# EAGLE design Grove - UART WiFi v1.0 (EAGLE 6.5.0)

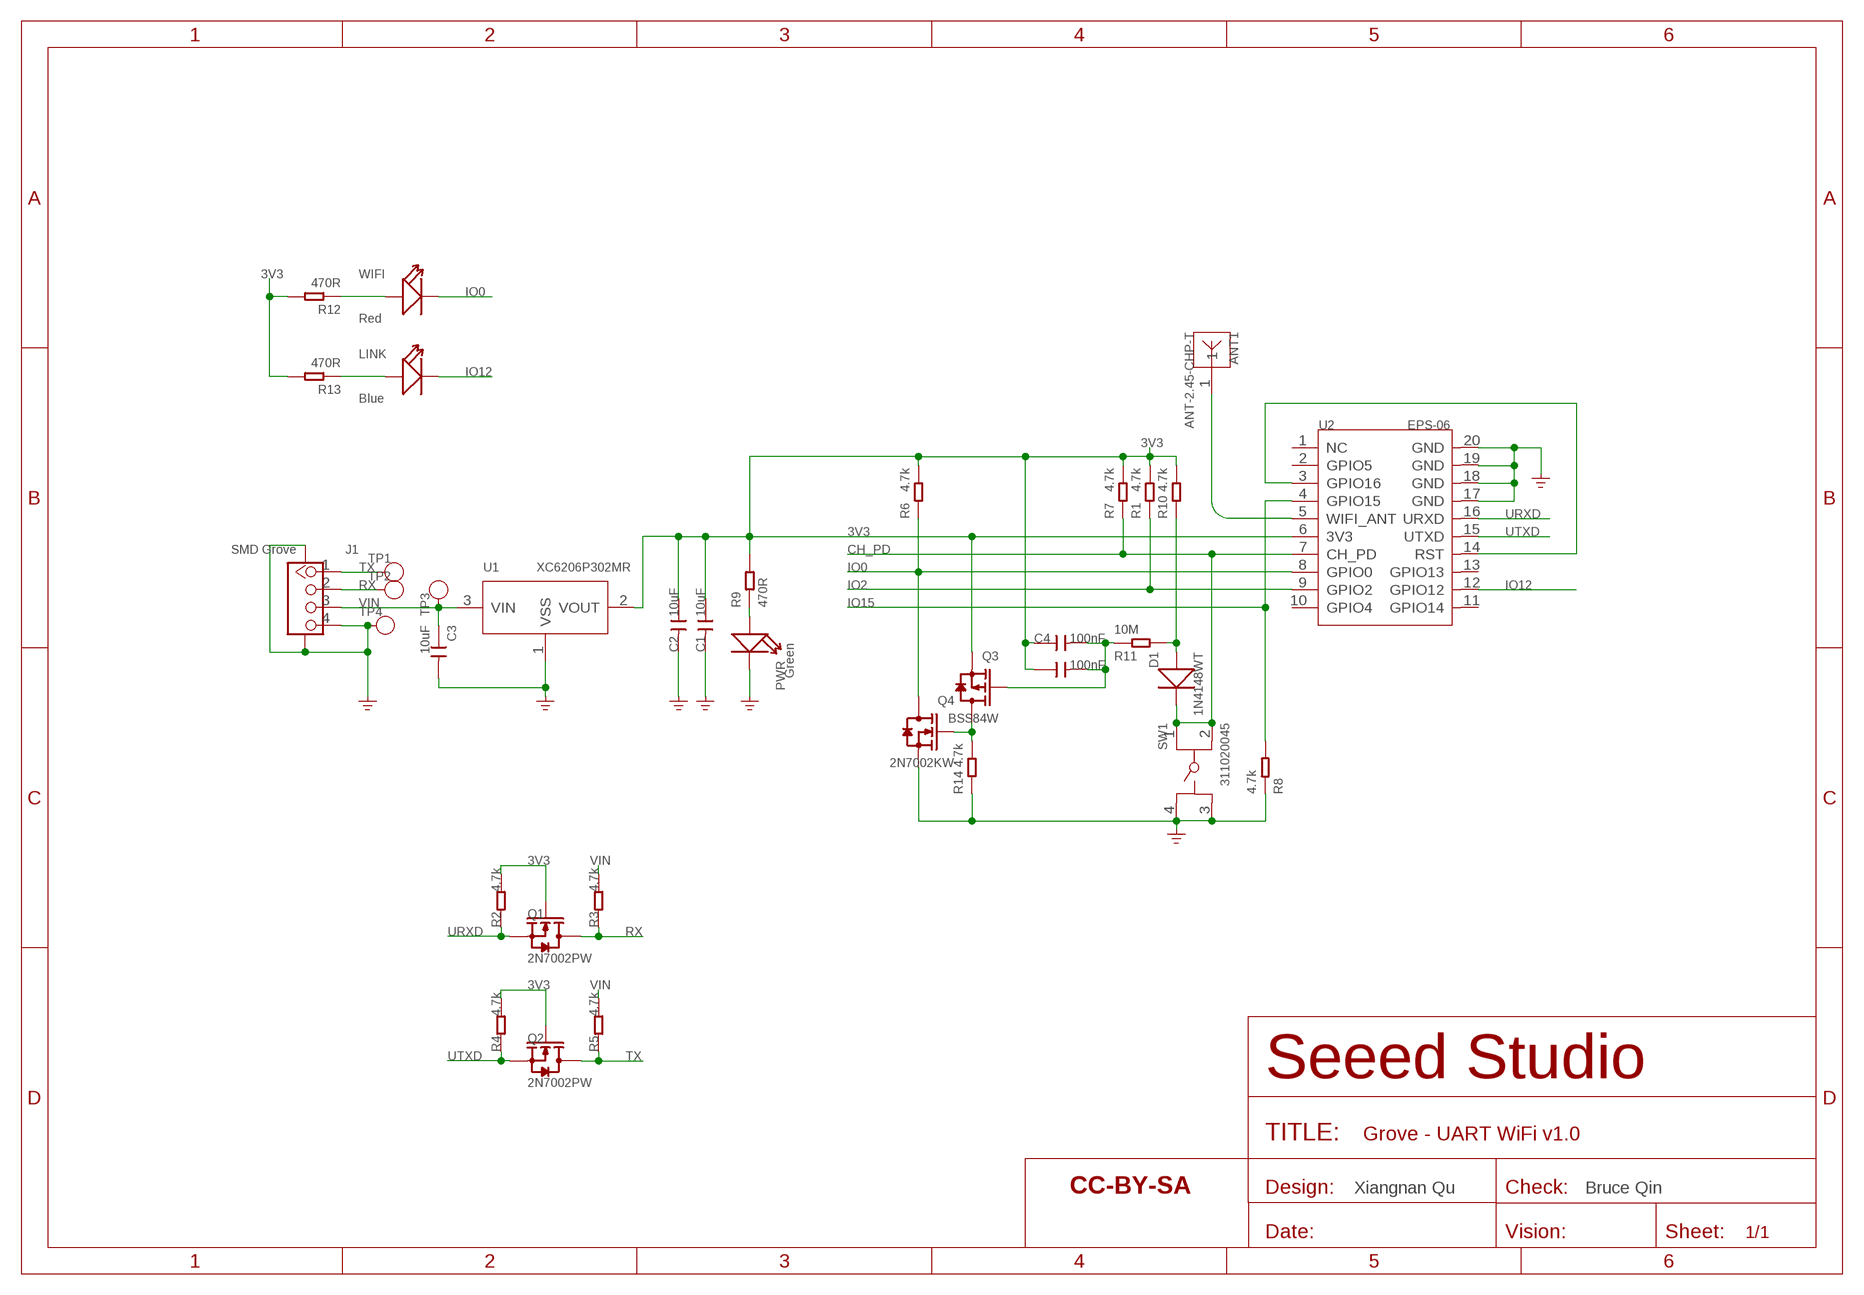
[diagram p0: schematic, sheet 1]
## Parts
ANT1  ANT-2.45-CHP-T  ANT-2.4G-CHP  [ANTENNA-2.4G-L6.5XW2.2MM]
C1  10uF  CAP-0805  [C0805]
C2  10uF  CAP-0805  [C0805]
C3  10uF  CAP-0805  [C0805]
C4  100nF  CAP-0402  [C0402]
C5  100nF  CAP-0402  [C0402]
D1  1N4148WT  DIODE'0603'  [SOD-523]
J1  SMD Grove  GROVE-CONNECTOR-SMD'DD'  [HW4-SMD-2.0]
LINK  Blue  LED'0402'  [LED-0402]
PWR  Green  LED'0402'  [LED-0402]
Q1  2N7002PW  MOSFET-N'SI1304BDL'  [SOT-323]
Q2  2N7002PW  MOSFET-N'SI1304BDL'  [SOT-323]
Q3  BSS84W  MOSFET-P-SOT323  [SOT-323]
Q4  2N7002KW  MOSFET-N'SI1304BDL'  [SOT-323]
R1  4.7k  RES-0402  [R0402]
R2  4.7k  RES-0402  [R0402]
R3  4.7k  RES-0402  [R0402]
R4  4.7k  RES-0402  [R0402]
R5  4.7k  RES-0402  [R0402]
R6  4.7k  RES-0402  [R0402]
R7  4.7k  RES-0402  [R0402]
R8  4.7k  RES-0402  [R0402]
R9  470R  RES-0402  [R0402]
R10  4.7k  RES-0402  [R0402]
R11  10M  RES-0402  [R0402]
R12  470R  RES-0402  [R0402]
R13  470R  RES-0402  [R0402]
R14  4.7k  RES-0402  [R0402]
SW1  311020045  BUTTON-4P  [BUTTON4P-SMD-4.5X3.2X2.5MM]
TP1  TEST-POINT'4545'  [TP-D45MIL]
TP2  TEST-POINT'4545'  [TP-D45MIL]
TP3  TEST-POINT'4545'  [TP-D45MIL]
TP4  TEST-POINT'4545'  [TP-D45MIL]
U1  XC6206P302MR  PMIC-XC6206PMR  [SOT-23]
U2  EPS-06  MOUDLE-WIFI-ESP8266_06  [WIFI20-SMD-16.3X13.1MM]
U$7  SEEEDSTUDIO-OPEN-SCH-FRAME  [SEEEDSTUDIO-PCB-FRAME]
WIFI  Red  LED'0402'  [LED-0402]

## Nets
3V3: C1.1 C2.1 C4.1 C5.1 Q1.1(G) Q2.1(G) Q3.2(S) R1.2 R2.2 R4.2 R6.2 R7.2 R9.2 R10.2 R12.2 R13.2 U1.2(VOUT) U2.6(3V3)
CH_PD: D1.- R7.1 SW1.1 SW1.2 U2.7(CH_PD)
GND: C1.2 C2.2 C3.2 J1.4 J1.SS1 J1.SS2 PWR.- Q4.2(S) R8.1 R14.1 SW1.3 SW1.4 TP4.T U1.1(VSS) U2.17(GND) U2.18(GND) U2.19(GND) U2.20(GND) ; supply symbol labelled GND_POWER
IO0: Q4.3(D) R6.1 U2.8(GPIO0) WIFI.-
IO2: R1.1 U2.9(GPIO2)
IO12: LINK.- U2.12(GPIO12)
IO15: R8.2 U2.4(GPIO15)
N$1: ANT1.1 U2.5(WIFI_ANT)
N$2: D1.+ R10.1 R11.2
N$3: PWR.+ R9.1
N$4: R12.1 WIFI.+
N$5: LINK.+ R13.1
N$6: Q3.3(D) Q4.1(G) R14.2
N$8: U2.3(GPIO16) U2.14(RST)
N$10: C4.2 C5.2 Q3.1(G) R11.1
RX: J1.2 Q1.3(D) R3.1 TP2.T
TX: J1.1 Q2.3(D) R5.1 TP1.T
URXD: Q1.2(S) R2.1 U2.16(URXD)
UTXD: Q2.2(S) R4.1 U2.15(UTXD)
VIN: C3.1 J1.3 R3.2 R5.2 TP3.T U1.3(VIN)
Unconnected: U2.1(NC) U2.2(GPIO5) U2.10(GPIO4) U2.11(GPIO14) U2.13(GPIO13)

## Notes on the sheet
- Xiangnan Qu | Bruce Qin

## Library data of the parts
ANT1 = template:ANT-2.4G-CHP
C1-C5 = Discrete-new:CAP: Ceramic Capacitors
D1 = Discrete-new:DIODE*
J1 = Connector-new:GROVE-CONNECTOR-SMD: 4P-SMD-2.0:320110030;4P-SMD-2.0-90D:320110032
LINK PWR WIFI = Discrete-new:LED
Q1 Q2 Q4 = Discrete-new:MOSFET-N
Q3 = Discrete-new:MOSFET-P
R1-R14 = Discrete-new:RES
SW1 = template:BUTTON-4P
TP1-TP4 = Discrete-new:TEST-POINT; PARTNO: DNP
U1 = IC-new:PMIC-XC6206P: LOW ESR Cap.Compatible Positive Voltage Regulators
U2 = template:MOUDLE-WIFI-ESP8266_06
U$7 = moudle-new:SEEEDSTUDIO-OPEN-SCH-FRAME

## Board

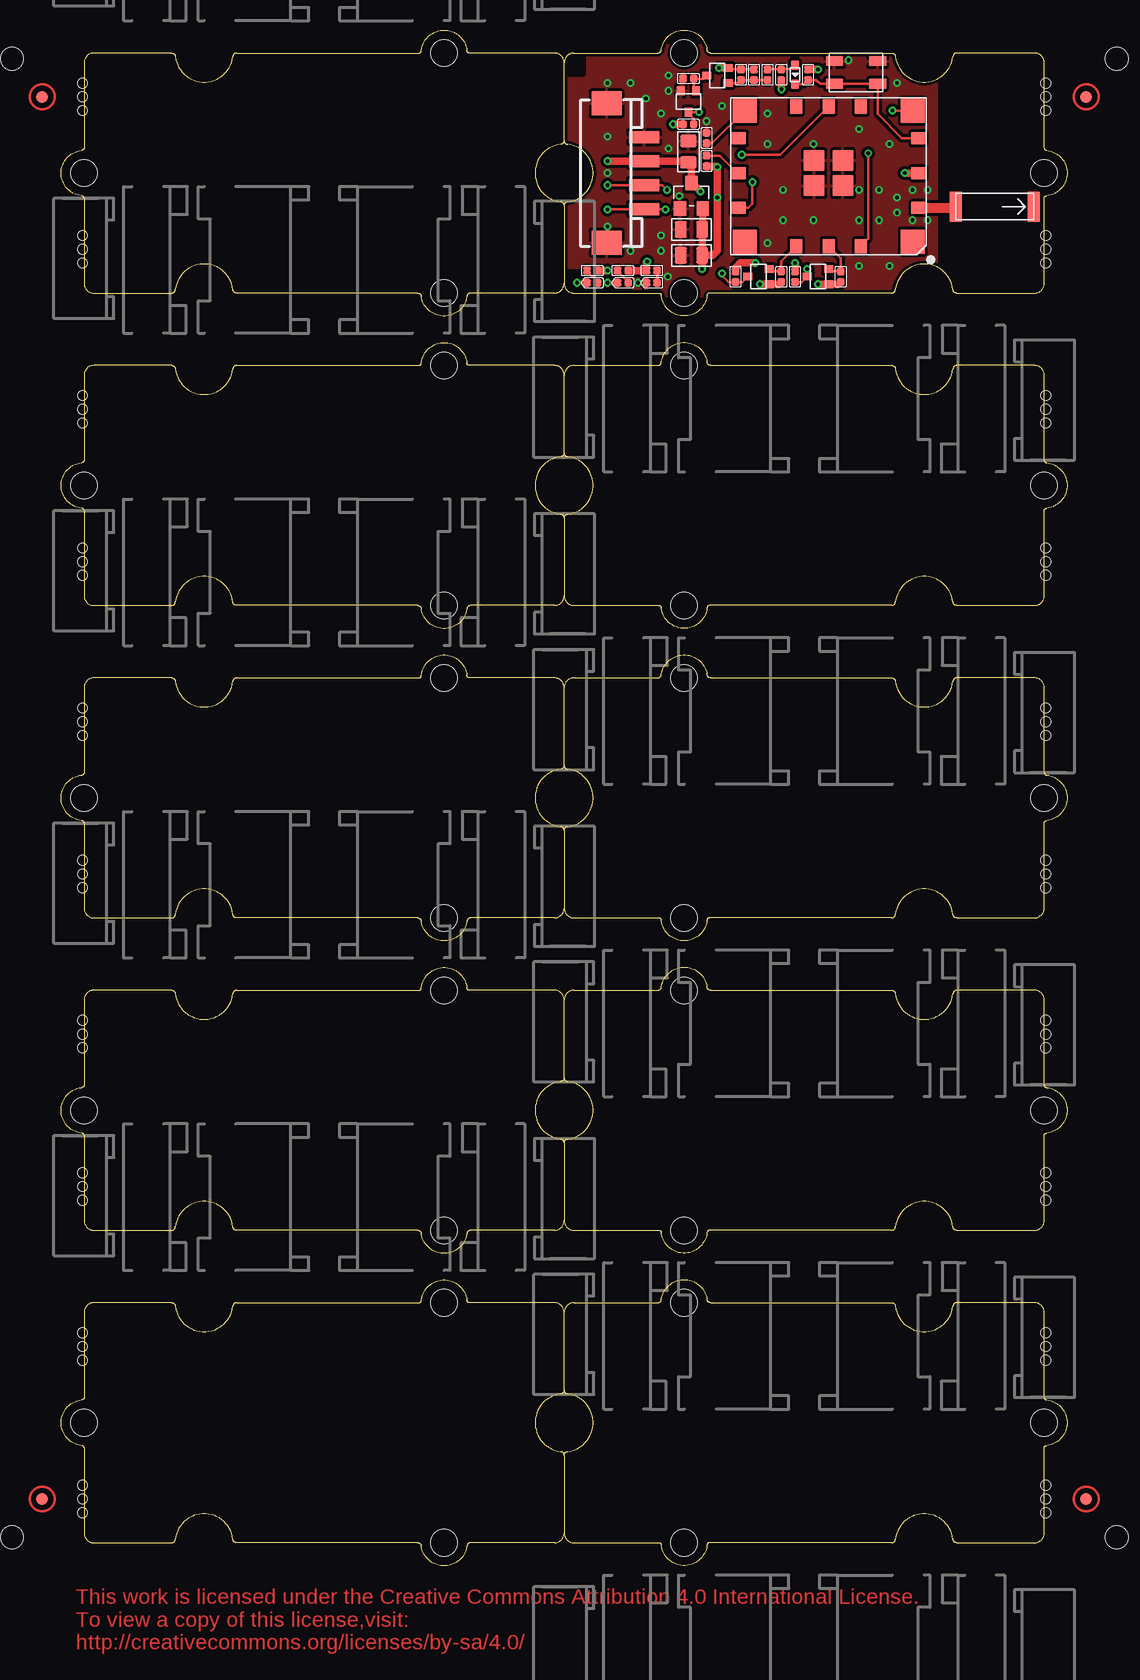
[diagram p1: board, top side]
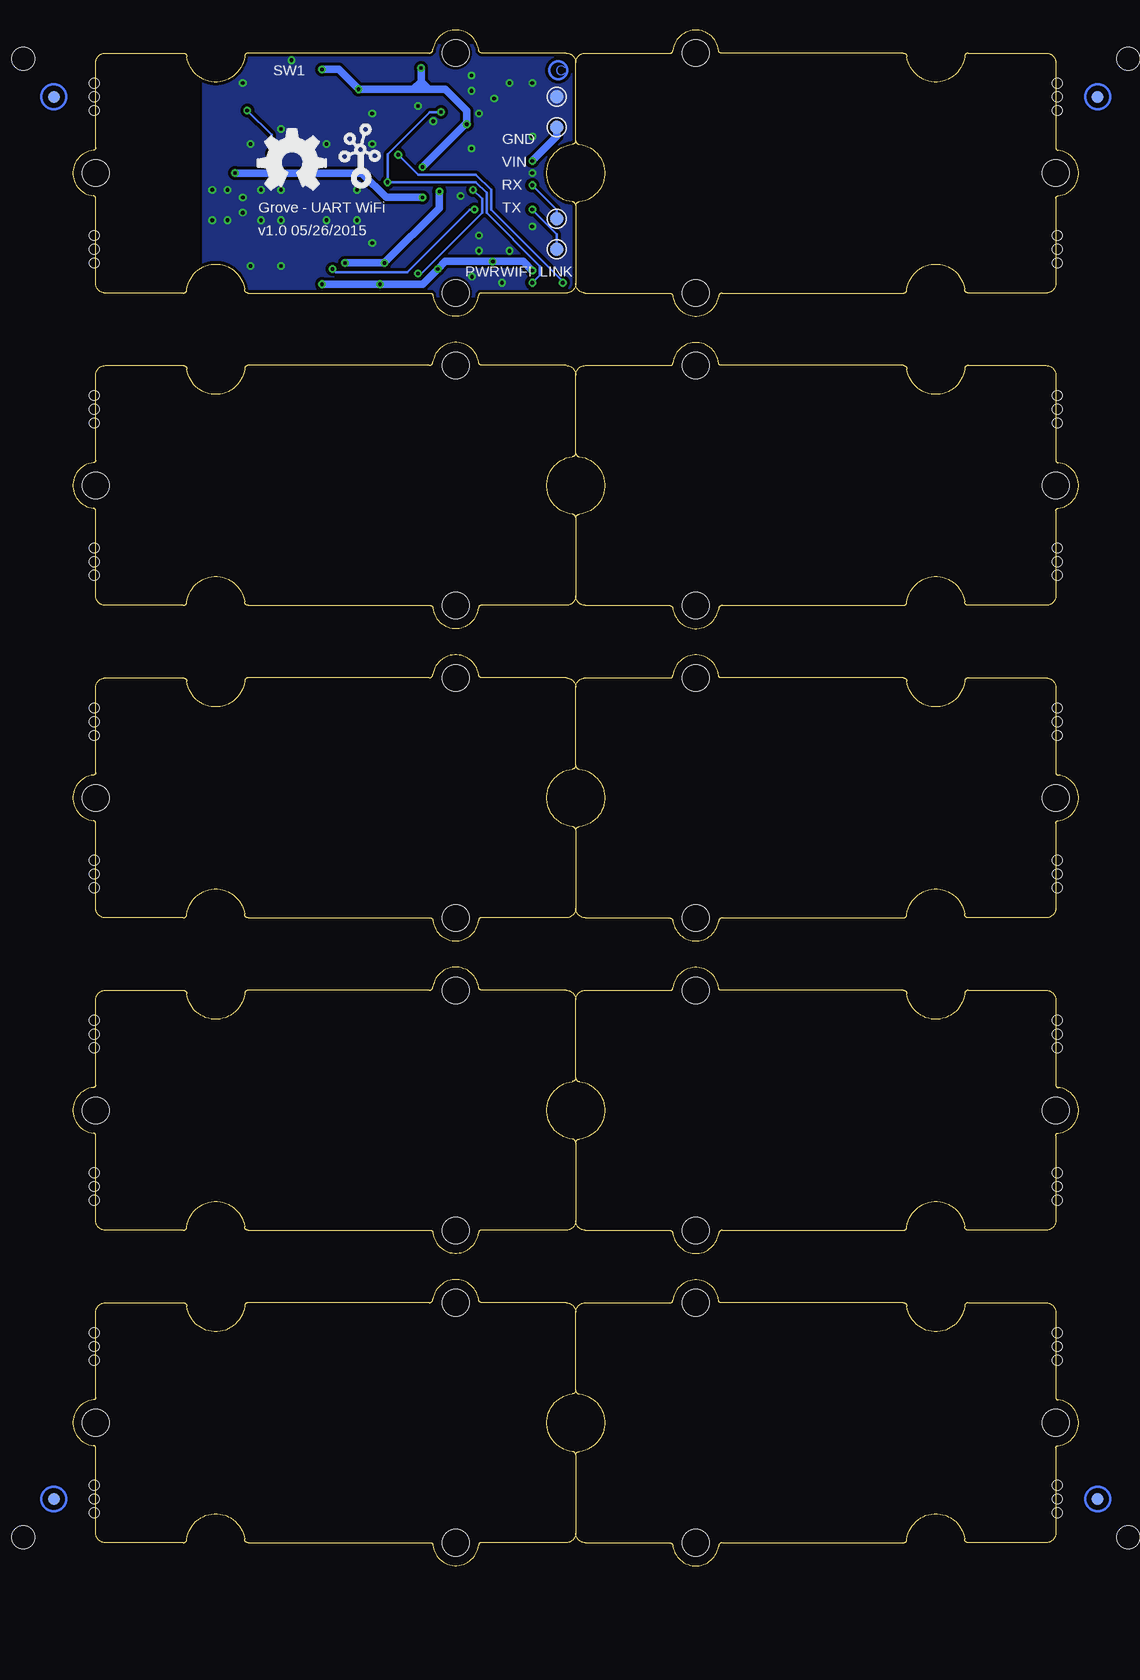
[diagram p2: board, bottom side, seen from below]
Size 83.82 x 127.98 mm. Coordinates in mm from the lower left corner, seen from the top.
Copper layers (1*16): Top 0.035mm / dielectric 1.5mm / Bottom 0.035mm
Design rules "SeeedStudio_2layer_DRU_no_angle_20140221 *": minimum track width 6mil, minimum drill 12mil, track to track 6mil, track to pad 6mil, pad to pad 6mil, via to via 6mil, smd to smd 0mil, copper to edge 10mil, drill to drill 10mil, minimum pad ring 10mil, minimum via ring 6mil, stop-mask expansion 2mil, vias tented up to drill 25mil, thermal gap 10mil
Holes 0.8 mm at 1.78,123.55 1.78,121.27 1.78,122.41 1.78,110.85 1.78,108.57 1.78,109.71 1.78,97.52 1.78,95.23 1.78,96.38 1.78,84.82 1.78,82.53 1.78,83.68 1.78,71.48 1.78,69.2 1.78,70.34 1.78,58.78 1.78,56.5 1.78,57.64 1.78,45.45 1.78,43.16 1.78,44.31 1.78,32.75 1.78,30.46 1.78,31.61 1.78,19.41 1.78,17.13 1.78,18.27 1.78,6.71 1.78,4.43 1.78,5.57 82.04,121.27 82.04,123.55 82.04,122.41 82.04,108.57 82.04,110.85 82.04,109.71 82.04,95.23 82.04,97.52 82.04,96.38 82.04,82.53 82.04,84.82 82.04,83.68 82.04,69.2 82.04,71.48 82.04,70.34 82.04,56.5 82.04,58.78 82.04,57.64 82.04,43.16 82.04,45.45 82.04,44.31 82.04,30.46 82.04,32.75 82.04,31.61 82.04,17.13 82.04,19.41 82.04,18.27 82.04,4.43 82.04,6.71 82.04,5.57
Holes 1.91 mm at -4.13,2.4 87.95,2.4 87.95,125.59 -4.13,125.59

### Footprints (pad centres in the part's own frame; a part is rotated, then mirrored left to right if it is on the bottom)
ANTENNA-2.4G-L6.5XW2.2MM = smd 2.5 x 1: 1 0,3.25; 2 0,-3.25
C0805 = smd 1.397 x 1.016: 1 0,0.889; 2 0,-0.889
C0402 = smd 0.635 x 0.635: 1 0,0.445; 2 0,-0.445
SOD-523 = smd 0.762 x 0.7: + -0.8,0; - 0.8,0
HW4-SMD-2.0 = smd 1 x 2.5: 1 -3,0; 2 -1,0; 3 1,0; 4 3,0 | smd 2 x 2.5: SS1 -5.8,3.123; SS2 5.8,3.123
LED-0402 = smd 0.635 x 0.635: + -0.445,0; - 0.445,0
ROUND-MARK-1.0 = smd 1.016 x 1.016: P$1 0,0
SOT-323 = smd 0.635 x 0.762: 1 -0.635,-0.889; 2 0.635,-0.889; 3 0,0.889
R0402 = smd 0.635 x 0.635: 1 0,0.445; 2 0,-0.445
BUTTON4P-SMD-4.5X3.2X2.5MM = smd 1.4 x 0.8: 1 -1.8,-0.94; 2 1.8,-0.94; 3 1.8,0.94; 4 -1.8,0.94
TP-D45MIL = smd 1.143 x 1.143: T 0,0
SOT-23 = smd 1.016 x 1.2: 1 -0.95,-1.06; 2 0.95,-1.06; 3 0,1.06
WIFI20-SMD-16.3X13.1MM = smd 2 x 2: 1 -7,5.708; 2 7,5.708; 3 -7,-5.2; 4 7,-5.2 | smd 1.2 x 1: 5 -7.493,2.9; 6 -7.493,0; 7 -7.493,-2.9; 8 7.493,2.9; 9 7.493,0; 10 7.493,-2.9 | smd 1 x 1.2: 11 -2.7,-5.558; 12 0,-5.558; 13 2.7,-5.558; 14 -2.7,6.096; 15 0,6.096; 16 2.7,6.096 | smd 1.7 x 1.7: 17 -1.2,1.05; 18 1.2,1.05; 19 -1.2,-1.05; 20 1.2,-1.05
GROVE-TEST-PLATFORM = hole 2.2: -10,-10; -10,10; 20,0
GROVE-1*2-TEST-PLATFORM = hole 2.2: -10,-10; -10,10; 20,0

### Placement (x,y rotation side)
ANT1  77.79,113.27 90 top
C1  52.52,109.2 270 top
C2  52.52,111.36 270 top
C3  52.26,117.84 180 top
C4  56.64,124.25 0 top
C5  57.72,124.25 0 top
D1  61.15,124.25 270 top
J1  48.58,116.06 90 top
LINK  44.26,106.92 180 top
P1  [ROUND-MARK-1.0]  -1.59,5.57 0 top
P2  [ROUND-MARK-1.0]  85.41,5.57 0 top
P3  [ROUND-MARK-1.0]  -1.59,122.41 0 top
P4  [ROUND-MARK-1.0]  85.41,122.41 0 top
P5  [ROUND-MARK-1.0]  -1.59,5.57 0 bottom
P6  [ROUND-MARK-1.0]  85.41,5.57 0 bottom
P7  [ROUND-MARK-1.0]  85.41,122.41 0 bottom
P8  [ROUND-MARK-1.0]  -1.59,122.41 0 bottom
PWR  49.21,106.92 180 top
Q1  58.1,107.43 90 top
Q2  63.06,107.43 90 top
Q3  54.67,124.19 90 top
Q4  52.26,122.03 180 top
R1  53.79,117.08 0 top
R2  60.01,107.43 0 top
R3  56.2,107.43 180 top
R4  64.96,107.43 0 top
R5  61.15,107.43 180 top
R6  52.26,120.13 270 top
R7  62.23,124.25 180 top
R8  53.79,118.98 0 top
R9  49.21,107.93 270 top
R10  60.01,124.25 0 top
R11  58.87,124.25 180 top
R12  46.8,107.93 90 top
R13  44.26,107.93 90 top
R14  52.26,123.94 90 top
SW1  66.23,124.44 0 top
TP1  43.5,109.71 0 bottom
TP2  43.5,112.25 0 bottom
TP3  43.5,119.87 0 bottom
TP4  43.5,122.41 0 bottom
U1  52.52,114.16 0 top
U2  63.95,116.06 180 top
U3  [GROVE-TEST-PLATFORM]  61.91,37.96 0 top
U4  [GROVE-TEST-PLATFORM]  21.91,37.96 180 top
U5  [GROVE-TEST-PLATFORM]  61.91,63.99 0 top
U6  [GROVE-TEST-PLATFORM]  21.91,63.99 180 top
U7  [GROVE-TEST-PLATFORM]  61.91,90.03 0 top
U8  [GROVE-TEST-PLATFORM]  21.91,90.03 180 top
U9  [GROVE-TEST-PLATFORM]  21.91,116.06 180 top
U10  [GROVE-TEST-PLATFORM]  61.91,116.06 0 top
U11  [GROVE-TEST-PLATFORM]  61.91,11.92 0 top
U12  [GROVE-TEST-PLATFORM]  21.91,11.92 180 top
U$7  not placed on the board
U$8  [GROVE-1*2-TEST-PLATFORM]  61.91,116.06 0 top
U$11  [GROVE-SILK-SMALL]  62.04,114.66 0 bottom
U$12  [OSHW_FILLX200_NOTEXT]  68.39,114.66 0 bottom
WIFI  46.8,106.92 180 top

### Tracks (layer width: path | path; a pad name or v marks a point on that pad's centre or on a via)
3V3  (via drill 0.3 pad 0.64)
  Top 0.203: C5.1 C4.1 55.56,124.7 Q3.2
  Top 0.61: U1.2 53.47,111.42 C2.1 C1.1 | R12.2 R9.2 48.77,108.63 v48.83,108.7 | R13.2 v45.53,107.93 | R6.2 v50.99,120.13 | Q3.2 v54.8,124.82 | R10.2 v60.01,123.05 | R7.2 v63.06,124.7 | R2.2 59.82,106.79 Q1.1 v58.23,106.79 | v63.06,106.79 Q2.1 64.77,106.79 R4.2 | v70.3,116.06 U2.6 | C1.1 54.29,109.2 54.67,109.58 v54.67,114.03 v54.67,116.57 54.61,116.63 R1.2 | C1.1 v53.4,108.06
  Bottom 0.61: v45.53,107.93 46.29,108.7 v48.83,108.7 52.77,108.7 v53.4,108.06 54.67,106.79 v58.23,106.79 v63.06,106.79 | 55.44,123.05 v60.01,123.05 61.66,124.7 v63.06,124.7 | 55.44,123.05 54.8,123.05 | 54.8,123.05 54.17,123.05 | 54.17,123.05 52.77,123.05 50.99,121.27 v50.99,120.13 51.12,120.13 v54.67,116.57 | v54.8,124.82 54.8,123.68 | 54.8,123.68 54.8,123.05 | 54.8,123.68 54.17,123.05 | 54.8,123.68 55.44,123.05 | v70.3,116.06 59.75,116.06 57.72,114.03 v54.67,114.03
CH_PD
  Top 0.203: D1.- 61.88,123.45 R7.1 62.93,123.81 63.23,123.5 SW1.1 SW1.2 68.03,120.99 70.06,118.96 U2.7
GND  (via drill 0.3 pad 0.64)
  other vias: 45.53,123.55 58.87,121.01 72.2,112.12 70.93,112.12 69.66,112.76 69.66,114.03 70.93,114.66 72.2,114.66 48.07,106.92 49.98,109.58 47.44,109.58 49.98,110.85 51.5,114.16 50.61,118.09 53.79,120.38 50.61,122.92 50.61,124.19 65.6,125.46 69.66,123.55 50.55,107.43 47.44,123.55 49.98,121.01 48.71,122.28 58.87,118.47 62.68,118.47 66.49,119.74 66.49,114.66 66.49,112.12 62.68,112.12 60.14,112.12 60.14,114.66 66.49,108.31 69.03,108.31 69.03,118.47 58.87,110.22 45.53,116.06 45.53,111.62 45.53,119.11 55.06,121.65 68.14,112.12 68.14,114.66
  pour Top (isolate 0.254, rank 6): 41.72,126.73 72.96,126.73 72.96,105.77 41.72,105.77
  pour Bottom (isolate 0.254, rank 6): 41.72,126.73 72.96,126.73 72.96,105.77 41.72,105.77
IO0  (via drill 0.3 pad 0.64)
  Top 0.203: WIFI.- v45.53,106.92 | v53.15,121.14 Q4.3 52.26,121.01 52.71,120.57 R6.1 | U2.8 57.24,113.16 57.6,113.52 v57.6,115.3
  Bottom 0.203: v53.15,121.14 54.08,121.14 57.6,117.63 v57.6,115.3 50.23,115.3 49.34,114.41 49.34,112.76 44.9,108.31 44.9,107.55 v45.53,106.92
IO2
  Top 0.203: R1.1 54.86,117.52 56.33,116.06 U2.9
IO12  (via drill 0.3 pad 0.64)
  Top 0.203: LINK.- v42.99,106.92 | U2.12 59.91,117.59 v56.71,117.59
  Bottom 0.203: v42.99,106.92 42.99,107.04 48.96,113.01 48.96,114.66 50.23,115.93 55.06,115.93 v56.71,117.59
IO15
  Top 0.203: R8.2 54.22,118.54 U2.4
N$1
  Top 0.406: 74.43,113.16 ANT1.1
  Top 0.813: U2.5 74.43,113.16
N$2
  Top 0.203: R11.2 R10.1 60.8,124.7 D1.+
N$3
  Top 0.203: PWR.+ R9.1
N$4
  Top 0.203: WIFI.+ 47.25,106.98 46.36,107.87 R12.1
N$5
  Top 0.203: LINK.+ 44.71,106.98 43.88,107.81 43.88,107.87 R13.1
N$6
  Top 0.203: Q4.1 52.71,123.11 R14.2 53.53,123.94 Q3.3
N$8  (via drill 0.3)
  Top 0.203: U2.3 v69.29,121.26 v69.28,121.27 | v67.25,117.71 67.25,110.57 U2.14
  Bottom 0.203: v69.28,121.27 67.25,119.24 v67.25,117.71
N$10
  Top 0.203: Q3.1 56.39,123.55 C4.2 C5.2 R11.1
RX  (via drill 0.3 pad 0.64)
  Top 0.203: Q1.3 56.77,106.98 R3.1 55.63,106.98 55.06,107.55 v55.06,107.68 | v50.48,114.66 50.09,115.06 J1.2 45.55,115.06 v45.53,115.05
  Bottom 0.203: v50.48,114.66 49.72,113.9 49.72,112.76 54.8,107.68 v55.06,107.68 | TP2.T 43.5,113.01 v45.53,115.05
TX  (via drill 0.3 pad 0.64)
  Top 0.203: R5.1 61.72,106.98 Q2.3 v62.17,108.06 | v50.36,113.01 50.31,113.06 J1.1 45.58,113.06 v45.53,113.01
  Bottom 0.203: v62.17,108.06 61.91,107.81 55.94,107.81 50.74,113.01 v50.36,113.01 | TP1.T 43.5,110.98 v45.53,113.01
URXD
  Top 0.203: U2.16 60.01,108.73 R2.1 59.18,107.87 Q1.2
UTXD
  Top 0.203: U2.15 64.96,108.95 R4.1 64.14,107.87 Q2.2
VIN  (via drill 0.3 pad 0.64)
  Top 0.61: R5.2 v61.15,108.57 | v57.85,108.57 56.58,108.57 56.2,108.19 R3.2 | v53.28,114.54 52.6,115.22 U1.3 52.52,116.7 C3.1 52.15,117.06 J1.3 45.55,117.06 v45.53,117.08
  Bottom 0.61: v61.15,108.57 v57.85,108.57 53.28,113.14 v53.28,114.54 | TP3.T 43.5,119.11 v45.53,117.08
(copper drawn outside any net)
  shapes: Bottom circle x1

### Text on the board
Bottom: C
bPlace: Grove - UART WiFi | v1.0 05/26/2015
bNames: GND | VIN | RX | TX
top_silk: SW1 | LINK | WIFI | PWR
